VERSION 5.8 ;
BUSBITCHARS "[]" ;
DIVIDERCHAR "/" ;

UNITS
  DATABASE MICRONS 1000 ;
END UNITS

MANUFACTURINGGRID 0.001 ;

PROPERTYDEFINITIONS
  LAYER LEF58_SPACINGTABLE STRING ;
END PROPERTYDEFINITIONS

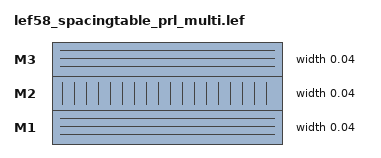
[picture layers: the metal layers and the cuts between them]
LAYER M1
  TYPE ROUTING ;
  DIRECTION HORIZONTAL ;
  WIDTH 0.04 ;
  MASK 2 ;
  PROPERTY LEF58_SPACINGTABLE "
    SPACINGTABLE PARALLELRUNLENGTH SAMEMASK -0.010 0.000 0.100
      WIDTH 0.000  0.060 0.070 0.070
      WIDTH 0.100  0.060 0.070 0.090 ;
    SPACINGTABLE PARALLELRUNLENGTH 0.000 0.100
      WIDTH 0.000  0.040 0.040
      WIDTH 0.100  0.040 0.090 ; " ;
END M1

LAYER M2
  TYPE ROUTING ;
  DIRECTION VERTICAL ;
  WIDTH 0.04 ;
  PROPERTY LEF58_SPACINGTABLE "
    SPACINGTABLE PARALLELRUNLENGTH 0.000 0.100
      WIDTH 0.000  0.040 0.040 ;
    SPACINGTABLE PARALLELRUNLENGTH 0.000 0.100
      WIDTH 0.000  0.040 ; " ;
END M2

LAYER M3
  TYPE ROUTING ;
  DIRECTION HORIZONTAL ;
  WIDTH 0.04 ;
  PROPERTY LEF58_SPACINGTABLE "
    SPACINGTABLE PARALLELRUNLENGTH 0.000 0.100
      WIDTH 0.000  0.040 0.040 ;
    SPACINGTABLE PARALLELRUNLENGTH 0.000 0.100
      0.040 0.040 ; " ;
END M3

END LIBRARY
